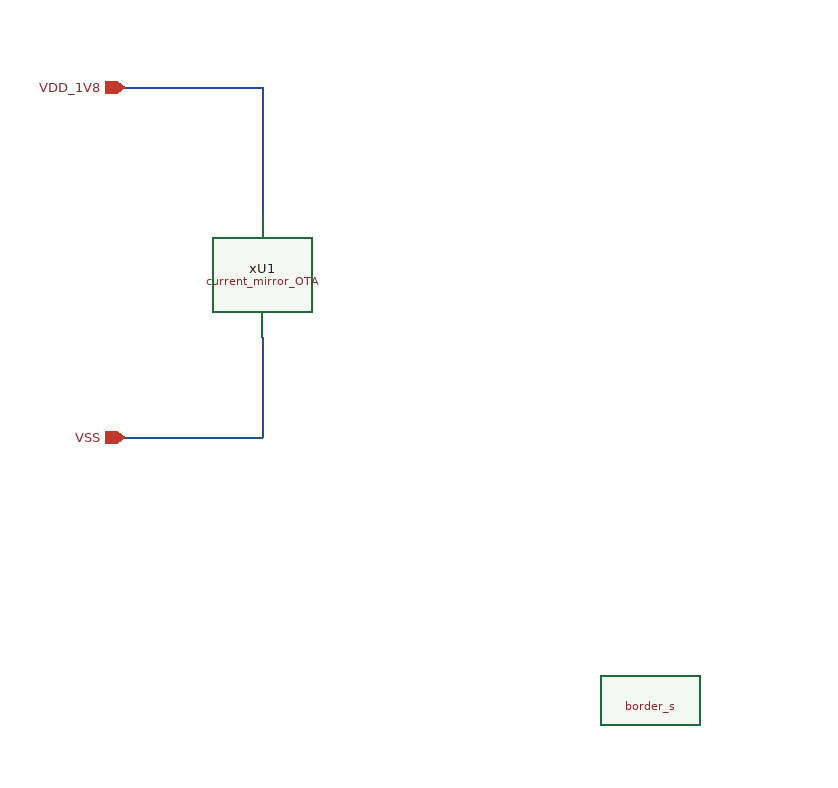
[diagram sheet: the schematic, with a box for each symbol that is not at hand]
v {xschem version=3.4.6 file_version=1.2}
G {}
K {}
V {}
S {}
E {}
N 1150 -720 1260 -720 {lab=VDD_1V8}
N 1150 -440 1260 -440 {lab=VSS}
N 1260 -720 1260 -620 {lab=VDD_1V8}
N 1260 -520 1260 -440 {lab=VSS}
C {cborder/border_s.sym} 1570 -230 0 0 {
user="Carsten Wulff"
company="Wulff Consulting AS"}
C {devices/ipin.sym} 1150 -720 0 0 {name=p1 lab=VDD_1V8}
C {devices/ipin.sym} 1150 -440 0 0 {name=p2 lab=VSS}
C {LELO_BKLE_IHP13G2/current_mirror_OTA.sym} 1140 -670 0 0 {name=xU1}
